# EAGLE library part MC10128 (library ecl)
ECL DEVICE

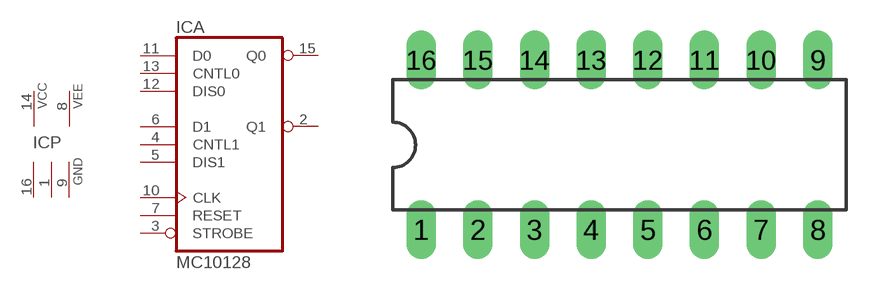
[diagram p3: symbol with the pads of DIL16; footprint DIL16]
Designator prefix IC; gates P=2PWR3GND A=MC10128

## MC10128  [DIL16]
1  P:GND  pwr
2  A:Q1  out
3  A:STROBE  in
4  A:CNTL1  in
5  A:DIS1  in
6  A:D1  in
7  A:RESET  in
8  P:VEE  pwr
9  P:GND  pwr
10  A:CLK  in
11  A:D0  in
12  A:DIS0  in
13  A:CNTL0  in
14  P:VCC  pwr
15  A:Q0  out
16  P:GND  pwr

## Footprint DIL16 (pad centres in mm)
Dual In Line Package
drill 0.813 long: 1 -8.89,-3.81; 2 -6.35,-3.81; 3 -3.81,-3.81; 4 -1.27,-3.81; 5 1.27,-3.81; 6 3.81,-3.81; 7 6.35,-3.81; 8 8.89,-3.81; 9 8.89,3.81; 10 6.35,3.81; 11 3.81,3.81; 12 1.27,3.81; 13 -1.27,3.81; 14 -3.81,3.81; 15 -6.35,3.81; 16 -8.89,3.81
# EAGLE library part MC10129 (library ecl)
ECL DEVICE

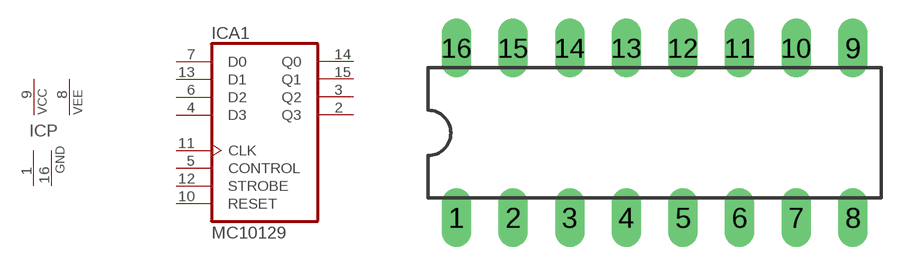
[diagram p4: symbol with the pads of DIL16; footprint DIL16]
Designator prefix IC; gates A1=MC10129 P=2PWR2GND

## MC10129  [DIL16]
1  P:GND  pwr
2  A1:Q3  out
3  A1:Q2  out
4  A1:D3  in
5  A1:CONTROL  in
6  A1:D2  in
7  A1:D0  in
8  P:VEE  pwr
9  P:VCC  pwr
10  A1:RESET  in
11  A1:CLK  in
12  A1:STROBE  in
13  A1:D1  in
14  A1:Q0  out
15  A1:Q1  out
16  P:GND  pwr

## Footprint DIL16 (pad centres in mm)
Dual In Line Package
drill 0.813 long: 1 -8.89,-3.81; 2 -6.35,-3.81; 3 -3.81,-3.81; 4 -1.27,-3.81; 5 1.27,-3.81; 6 3.81,-3.81; 7 6.35,-3.81; 8 8.89,-3.81; 9 8.89,3.81; 10 6.35,3.81; 11 3.81,3.81; 12 1.27,3.81; 13 -1.27,3.81; 14 -3.81,3.81; 15 -6.35,3.81; 16 -8.89,3.81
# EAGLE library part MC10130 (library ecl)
ECL DEVICE

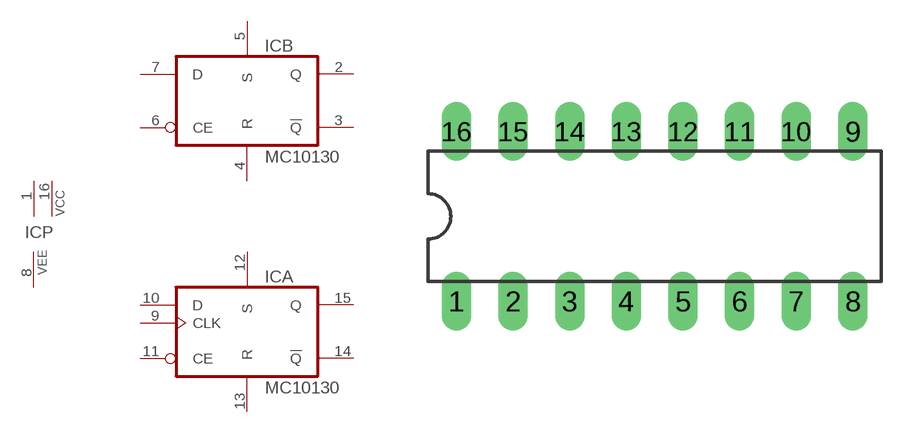
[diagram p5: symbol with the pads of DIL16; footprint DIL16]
Designator prefix IC; gates P=2VCC1VEE A=MC10130 B=MC10130 C=CLK

## MC10130  [DIL16]
1  P:VCC  pwr
2  B:Q  out
3  B:!Q  out
4  B:R  in
5  B:S  in
6  B:CE  in
7  B:D  in
8  P:VEE  pwr
9  C:CLK  in
10  A:D  in
11  A:CE  in
12  A:S  in
13  A:R  in
14  A:!Q  out
15  A:Q  out
16  P:VCC  pwr

## Footprint DIL16 (pad centres in mm)
Dual In Line Package
drill 0.813 long: 1 -8.89,-3.81; 2 -6.35,-3.81; 3 -3.81,-3.81; 4 -1.27,-3.81; 5 1.27,-3.81; 6 3.81,-3.81; 7 6.35,-3.81; 8 8.89,-3.81; 9 8.89,3.81; 10 6.35,3.81; 11 3.81,3.81; 12 1.27,3.81; 13 -1.27,3.81; 14 -3.81,3.81; 15 -6.35,3.81; 16 -8.89,3.81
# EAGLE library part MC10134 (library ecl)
ECL DEVICE

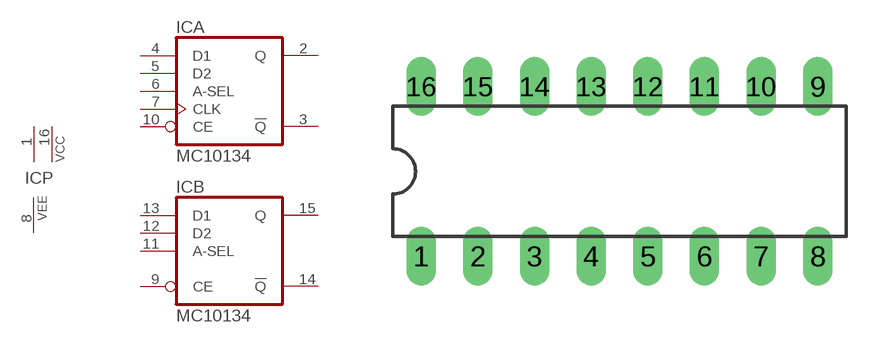
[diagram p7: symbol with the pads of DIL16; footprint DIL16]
Designator prefix IC; gates P=2VCC1VEE A=MC10134 B=MC10134 A1=CLK

## MC10134  [DIL16]
1  P:VCC  pwr
2  A:Q  out
3  A:!Q  out
4  A:D1  in
5  A:D2  in
6  A:A-SEL  in
7  A1:CLK  in
8  P:VEE  pwr
9  B:CE  in
10  A:CE  in
11  B:A-SEL  in
12  B:D2  in
13  B:D1  in
14  B:!Q  out
15  B:Q  out
16  P:VCC  pwr

## Footprint DIL16 (pad centres in mm)
Dual In Line Package
drill 0.813 long: 1 -8.89,-3.81; 2 -6.35,-3.81; 3 -3.81,-3.81; 4 -1.27,-3.81; 5 1.27,-3.81; 6 3.81,-3.81; 7 6.35,-3.81; 8 8.89,-3.81; 9 8.89,3.81; 10 6.35,3.81; 11 3.81,3.81; 12 1.27,3.81; 13 -1.27,3.81; 14 -3.81,3.81; 15 -6.35,3.81; 16 -8.89,3.81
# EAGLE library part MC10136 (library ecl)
ECL DEVICE

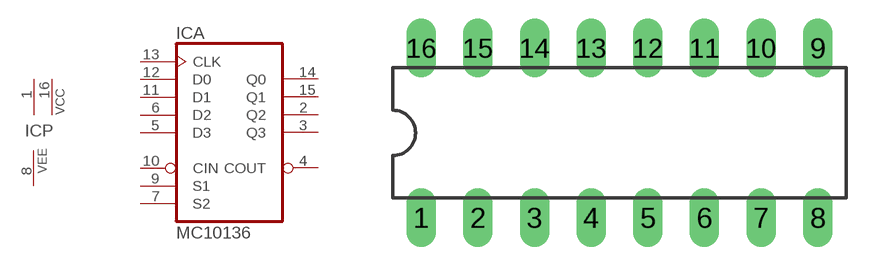
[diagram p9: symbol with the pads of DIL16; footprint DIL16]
Designator prefix IC; gates A=MC10136 P=2VCC1VEE

## MC10136  [DIL16]
1  P:VCC  pwr
2  A:Q2  out
3  A:Q3  out
4  A:COUT  out
5  A:D3  in
6  A:D2  in
7  A:S2  in
8  P:VEE  pwr
9  A:S1  in
10  A:CIN  in
11  A:D1  in
12  A:D0  in
13  A:CLK  in
14  A:Q0  out
15  A:Q1  out
16  P:VCC  pwr

## Footprint DIL16 (pad centres in mm)
Dual In Line Package
drill 0.813 long: 1 -8.89,-3.81; 2 -6.35,-3.81; 3 -3.81,-3.81; 4 -1.27,-3.81; 5 1.27,-3.81; 6 3.81,-3.81; 7 6.35,-3.81; 8 8.89,-3.81; 9 8.89,3.81; 10 6.35,3.81; 11 3.81,3.81; 12 1.27,3.81; 13 -1.27,3.81; 14 -3.81,3.81; 15 -6.35,3.81; 16 -8.89,3.81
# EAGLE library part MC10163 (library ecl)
ECL DEVICE

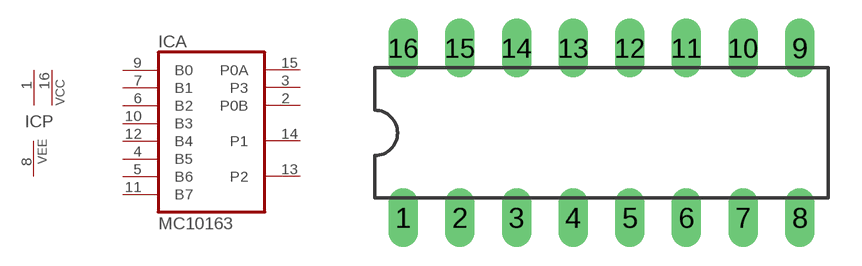
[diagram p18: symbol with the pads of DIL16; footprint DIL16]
Designator prefix IC; gates A=MC10163 P=2VCC1VEE

## MC10163  [DIL16]
1  P:VCC  pwr
2  A:P0B  out
3  A:P3  out
4  A:B5  in
5  A:B6  in
6  A:B2  in
7  A:B1  in
8  P:VEE  pwr
9  A:B0  in
10  A:B3  in
11  A:B7  in
12  A:B4  in
13  A:P2  out
14  A:P1  out
15  A:P0A  out
16  P:VCC  pwr

## Footprint DIL16 (pad centres in mm)
Dual In Line Package
drill 0.813 long: 1 -8.89,-3.81; 2 -6.35,-3.81; 3 -3.81,-3.81; 4 -1.27,-3.81; 5 1.27,-3.81; 6 3.81,-3.81; 7 6.35,-3.81; 8 8.89,-3.81; 9 8.89,3.81; 10 6.35,3.81; 11 3.81,3.81; 12 1.27,3.81; 13 -1.27,3.81; 14 -3.81,3.81; 15 -6.35,3.81; 16 -8.89,3.81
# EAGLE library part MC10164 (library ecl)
ECL DEVICE

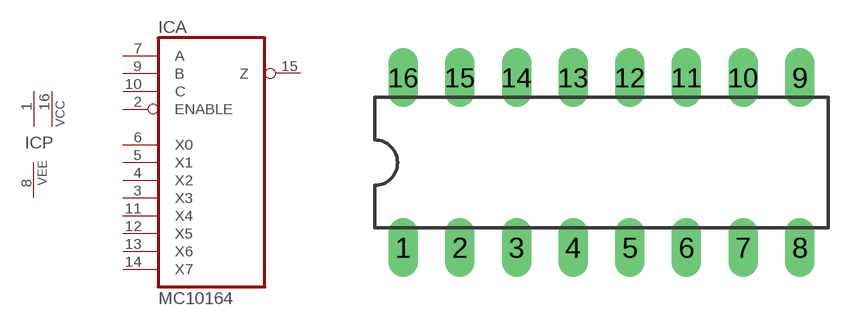
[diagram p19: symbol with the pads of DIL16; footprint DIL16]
Designator prefix IC; gates A=MC10164 P=2VCC1VEE

## MC10164  [DIL16]
1  P:VCC  pwr
2  A:ENABLE  in
3  A:X3  in
4  A:X2  in
5  A:X1  in
6  A:X0  in
7  A:A  in
8  P:VEE  pwr
9  A:B  in
10  A:C  in
11  A:X4  in
12  A:X5  in
13  A:X6  in
14  A:X7  in
15  A:Z  out
16  P:VCC  pwr

## Footprint DIL16 (pad centres in mm)
Dual In Line Package
drill 0.813 long: 1 -8.89,-3.81; 2 -6.35,-3.81; 3 -3.81,-3.81; 4 -1.27,-3.81; 5 1.27,-3.81; 6 3.81,-3.81; 7 6.35,-3.81; 8 8.89,-3.81; 9 8.89,3.81; 10 6.35,3.81; 11 3.81,3.81; 12 1.27,3.81; 13 -1.27,3.81; 14 -3.81,3.81; 15 -6.35,3.81; 16 -8.89,3.81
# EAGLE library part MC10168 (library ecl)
ECL DEVICE

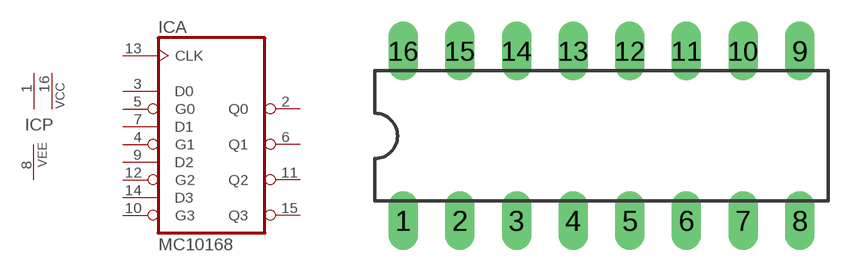
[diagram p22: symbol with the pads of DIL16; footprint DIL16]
Designator prefix IC; gates A=MC10168 P=2VCC1VEE

## MC10168  [DIL16]
1  P:VCC  pwr
2  A:Q0  out
3  A:D0  in
4  A:G1  in
5  A:G0  in
6  A:Q1  out
7  A:D1  in
8  P:VEE  pwr
9  A:D2  in
10  A:G3  in
11  A:Q2  out
12  A:G2  in
13  A:CLK  in
14  A:D3  in
15  A:Q3  out
16  P:VCC  pwr

## Footprint DIL16 (pad centres in mm)
Dual In Line Package
drill 0.813 long: 1 -8.89,-3.81; 2 -6.35,-3.81; 3 -3.81,-3.81; 4 -1.27,-3.81; 5 1.27,-3.81; 6 3.81,-3.81; 7 6.35,-3.81; 8 8.89,-3.81; 9 8.89,3.81; 10 6.35,3.81; 11 3.81,3.81; 12 1.27,3.81; 13 -1.27,3.81; 14 -3.81,3.81; 15 -6.35,3.81; 16 -8.89,3.81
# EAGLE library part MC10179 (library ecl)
ECL DEVICE

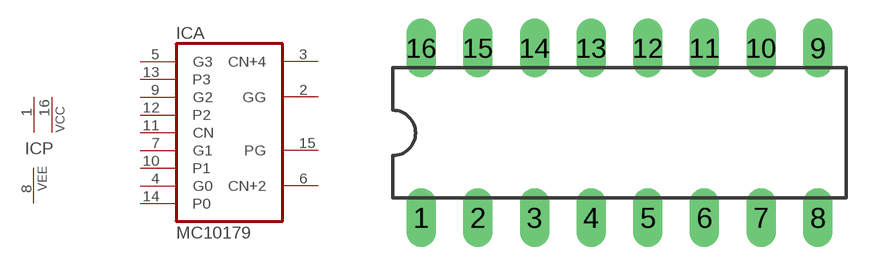
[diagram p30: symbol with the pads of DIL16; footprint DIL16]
Designator prefix IC; gates A=MC10179 P=2VCC1VEE

## MC10179  [DIL16]
1  P:VCC  pwr
2  A:GG  out
3  A:CN+4  out
4  A:G0  in
5  A:G3  in
6  A:CN+2  out
7  A:G1  in
8  P:VEE  pwr
9  A:G2  in
10  A:P1  in
11  A:CN  in
12  A:P2  in
13  A:P3  in
14  A:P0  in
15  A:PG  out
16  P:VCC  pwr

## Footprint DIL16 (pad centres in mm)
Dual In Line Package
drill 0.813 long: 1 -8.89,-3.81; 2 -6.35,-3.81; 3 -3.81,-3.81; 4 -1.27,-3.81; 5 1.27,-3.81; 6 3.81,-3.81; 7 6.35,-3.81; 8 8.89,-3.81; 9 8.89,3.81; 10 6.35,3.81; 11 3.81,3.81; 12 1.27,3.81; 13 -1.27,3.81; 14 -3.81,3.81; 15 -6.35,3.81; 16 -8.89,3.81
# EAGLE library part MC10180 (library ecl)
ECL DEVICE

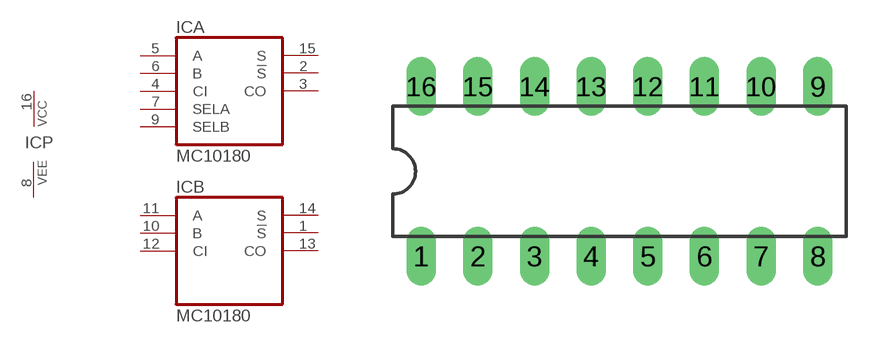
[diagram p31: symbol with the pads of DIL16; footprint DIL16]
Designator prefix IC; gates P=1VCC1VEE A=MC10180 B=MC10180 A1=SELAB

## MC10180  [DIL16]
1  B:!S  out
2  A:!S  out
3  A:CO  out
4  A:CI  in
5  A:A  in
6  A:B  in
7  A1:SELA  in
8  P:VEE  pwr
9  A1:SELB  in
10  B:B  in
11  B:A  in
12  B:CI  in
13  B:CO  out
14  B:S  out
15  A:S  out
16  P:VCC  pwr

## Footprint DIL16 (pad centres in mm)
Dual In Line Package
drill 0.813 long: 1 -8.89,-3.81; 2 -6.35,-3.81; 3 -3.81,-3.81; 4 -1.27,-3.81; 5 1.27,-3.81; 6 3.81,-3.81; 7 6.35,-3.81; 8 8.89,-3.81; 9 8.89,3.81; 10 6.35,3.81; 11 3.81,3.81; 12 1.27,3.81; 13 -1.27,3.81; 14 -3.81,3.81; 15 -6.35,3.81; 16 -8.89,3.81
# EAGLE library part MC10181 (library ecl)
ECL DEVICE

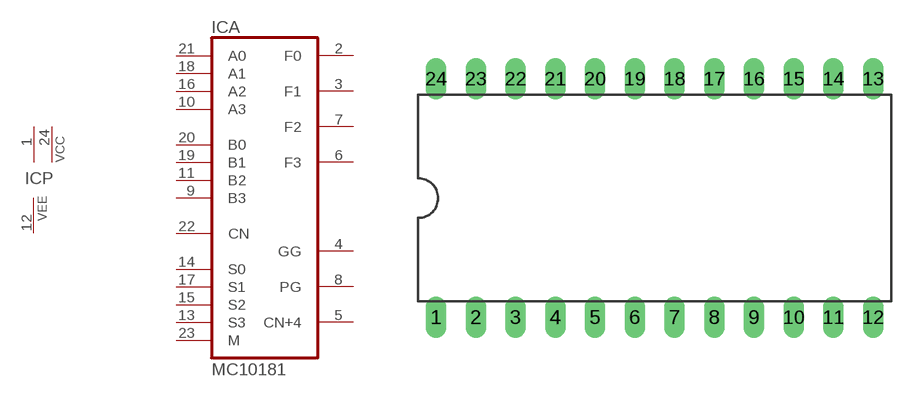
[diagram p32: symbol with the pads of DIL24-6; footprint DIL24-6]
Designator prefix IC; gates A=MC10181 P=2VCC1VEE

## MC10181  [DIL24-6]
1  P:VCC  pwr
2  A:F0  out
3  A:F1  out
4  A:GG  out
5  A:CN+4  out
6  A:F3  out
7  A:F2  out
8  A:PG  out
9  A:B3  in
10  A:A3  in
11  A:B2  in
12  P:VEE  pwr
13  A:S3  in
14  A:S0  in
15  A:S2  in
16  A:A2  in
17  A:S1  in
18  A:A1  in
19  A:B1  in
20  A:B0  in
21  A:A0  in
22  A:CN  in
23  A:M  in
24  P:VCC  pwr

## Footprint DIL24-6 (pad centres in mm)
Dual In Line Package 0.6 inch
drill 0.813 long: 1 -13.97,-7.62; 2 -11.43,-7.62; 3 -8.89,-7.62; 4 -6.35,-7.62; 5 -3.81,-7.62; 6 -1.27,-7.62; 7 1.27,-7.62; 8 3.81,-7.62; 9 6.35,-7.62; 10 8.89,-7.62; 11 11.43,-7.62; 12 13.97,-7.62; 13 13.97,7.62; 14 11.43,7.62; 15 8.89,7.62; 16 6.35,7.62; 17 3.81,7.62; 18 1.27,7.62; 19 -1.27,7.62; 20 -3.81,7.62; 21 -6.35,7.62; 22 -8.89,7.62; 23 -11.43,7.62; 24 -13.97,7.62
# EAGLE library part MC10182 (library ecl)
ECL DEVICE

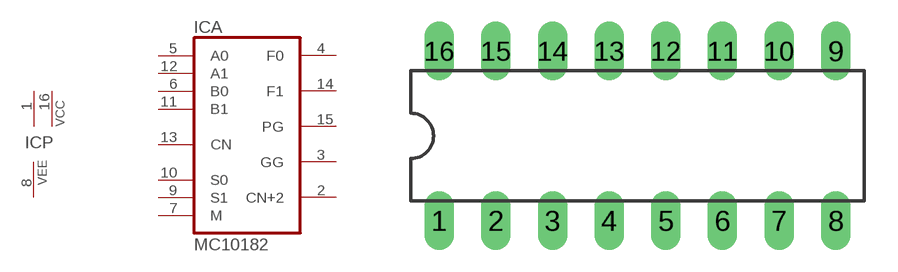
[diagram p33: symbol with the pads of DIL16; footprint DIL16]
Designator prefix IC; gates A=MC10182 P=2VCC1VEE

## MC10182  [DIL16]
1  P:VCC  pwr
2  A:CN+2  out
3  A:GG  out
4  A:F0  out
5  A:A0  in
6  A:B0  in
7  A:M  in
8  P:VEE  pwr
9  A:S1  in
10  A:S0  in
11  A:B1  in
12  A:A1  in
13  A:CN  in
14  A:F1  out
15  A:PG  out
16  P:VCC  pwr

## Footprint DIL16 (pad centres in mm)
Dual In Line Package
drill 0.813 long: 1 -8.89,-3.81; 2 -6.35,-3.81; 3 -3.81,-3.81; 4 -1.27,-3.81; 5 1.27,-3.81; 6 3.81,-3.81; 7 6.35,-3.81; 8 8.89,-3.81; 9 8.89,3.81; 10 6.35,3.81; 11 3.81,3.81; 12 1.27,3.81; 13 -1.27,3.81; 14 -3.81,3.81; 15 -6.35,3.81; 16 -8.89,3.81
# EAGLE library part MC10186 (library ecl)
ECL DEVICE

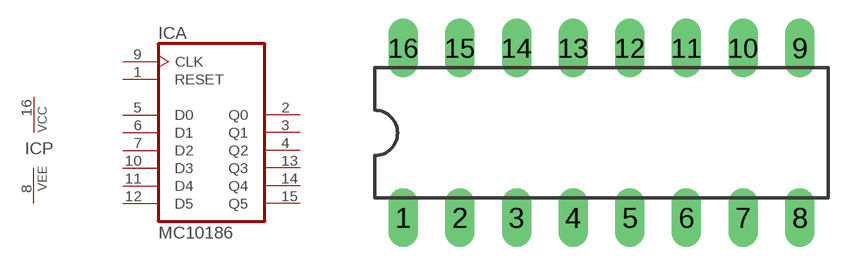
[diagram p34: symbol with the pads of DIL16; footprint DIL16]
Designator prefix IC; gates A=MC10186 P=1VCC1VEE

## MC10186  [DIL16]
1  A:RESET  in
2  A:Q0  out
3  A:Q1  out
4  A:Q2  out
5  A:D0  in
6  A:D1  in
7  A:D2  in
8  P:VEE  pwr
9  A:CLK  in
10  A:D3  in
11  A:D4  in
12  A:D5  in
13  A:Q3  out
14  A:Q4  out
15  A:Q5  out
16  P:VCC  pwr

## Footprint DIL16 (pad centres in mm)
Dual In Line Package
drill 0.813 long: 1 -8.89,-3.81; 2 -6.35,-3.81; 3 -3.81,-3.81; 4 -1.27,-3.81; 5 1.27,-3.81; 6 3.81,-3.81; 7 6.35,-3.81; 8 8.89,-3.81; 9 8.89,3.81; 10 6.35,3.81; 11 3.81,3.81; 12 1.27,3.81; 13 -1.27,3.81; 14 -3.81,3.81; 15 -6.35,3.81; 16 -8.89,3.81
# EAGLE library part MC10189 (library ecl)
ECL DEVICE

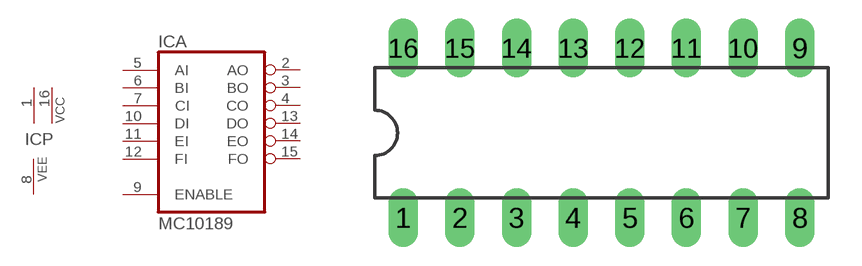
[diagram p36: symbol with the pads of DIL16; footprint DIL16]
Designator prefix IC; gates A=MC10189 P=2VCC1VEE

## MC10189  [DIL16]
1  P:VCC  pwr
2  A:AO  out
3  A:BO  out
4  A:CO  out
5  A:AI  in
6  A:BI  in
7  A:CI  in
8  P:VEE  pwr
9  A:ENABLE  in
10  A:DI  in
11  A:EI  in
12  A:FI  in
13  A:DO  out
14  A:EO  out
15  A:FO  out
16  P:VCC  pwr

## Footprint DIL16 (pad centres in mm)
Dual In Line Package
drill 0.813 long: 1 -8.89,-3.81; 2 -6.35,-3.81; 3 -3.81,-3.81; 4 -1.27,-3.81; 5 1.27,-3.81; 6 3.81,-3.81; 7 6.35,-3.81; 8 8.89,-3.81; 9 8.89,3.81; 10 6.35,3.81; 11 3.81,3.81; 12 1.27,3.81; 13 -1.27,3.81; 14 -3.81,3.81; 15 -6.35,3.81; 16 -8.89,3.81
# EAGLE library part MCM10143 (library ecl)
ECL DEVICE

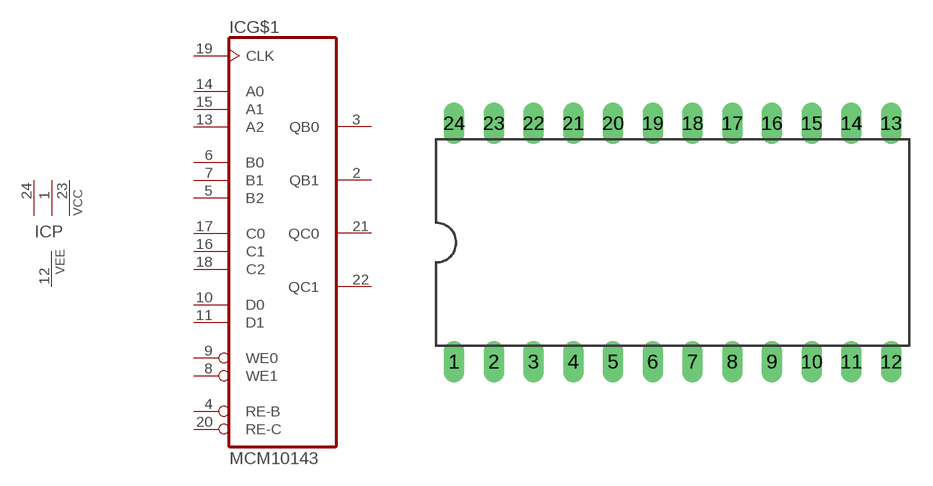
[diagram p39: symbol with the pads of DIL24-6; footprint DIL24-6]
Designator prefix IC; gates G$1=MCM10143 P=3VCC1VEE

## MCM10143  [DIL24-6]
1  P:VCC  pwr
2  G$1:QB1  out
3  G$1:QB0  out
4  G$1:RE-B  in
5  G$1:B2  in
6  G$1:B0  in
7  G$1:B1  in
8  G$1:WE1  in
9  G$1:WE0  in
10  G$1:D0  in
11  G$1:D1  in
12  P:VEE  pwr
13  G$1:A2  in
14  G$1:A0  in
15  G$1:A1  in
16  G$1:C1  in
17  G$1:C0  in
18  G$1:C2  in
19  G$1:CLK  in
20  G$1:RE-C  in
21  G$1:QC0  out
22  G$1:QC1  out
23  P:VCC  pwr
24  P:VCC  pwr

## Footprint DIL24-6 (pad centres in mm)
Dual In Line Package 0.6 inch
drill 0.813 long: 1 -13.97,-7.62; 2 -11.43,-7.62; 3 -8.89,-7.62; 4 -6.35,-7.62; 5 -3.81,-7.62; 6 -1.27,-7.62; 7 1.27,-7.62; 8 3.81,-7.62; 9 6.35,-7.62; 10 8.89,-7.62; 11 11.43,-7.62; 12 13.97,-7.62; 13 13.97,7.62; 14 11.43,7.62; 15 8.89,7.62; 16 6.35,7.62; 17 3.81,7.62; 18 1.27,7.62; 19 -1.27,7.62; 20 -3.81,7.62; 21 -6.35,7.62; 22 -8.89,7.62; 23 -11.43,7.62; 24 -13.97,7.62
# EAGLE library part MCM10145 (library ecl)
ECL DEVICE

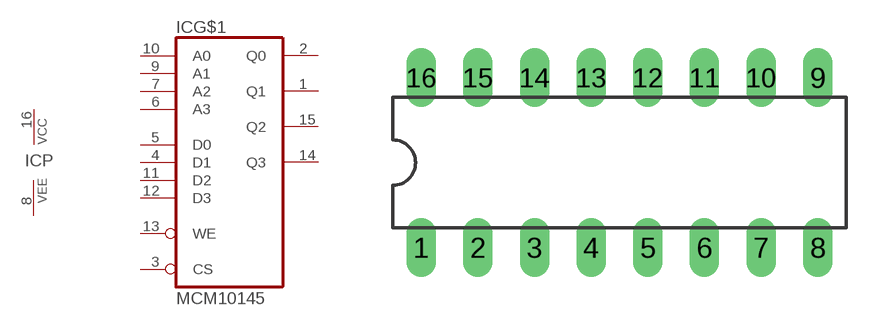
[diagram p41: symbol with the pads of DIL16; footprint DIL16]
Designator prefix IC; gates G$1=MCM10145 P=1VCC1VEE

## MCM10145  [DIL16]
1  G$1:Q1  out
2  G$1:Q0  out
3  G$1:CS  in
4  G$1:D1  in
5  G$1:D0  in
6  G$1:A3  in
7  G$1:A2  in
8  P:VEE  pwr
9  G$1:A1  in
10  G$1:A0  in
11  G$1:D2  in
12  G$1:D3  in
13  G$1:WE  in
14  G$1:Q3  out
15  G$1:Q2  out
16  P:VCC  pwr

## Footprint DIL16 (pad centres in mm)
Dual In Line Package
drill 0.813 long: 1 -8.89,-3.81; 2 -6.35,-3.81; 3 -3.81,-3.81; 4 -1.27,-3.81; 5 1.27,-3.81; 6 3.81,-3.81; 7 6.35,-3.81; 8 8.89,-3.81; 9 8.89,3.81; 10 6.35,3.81; 11 3.81,3.81; 12 1.27,3.81; 13 -1.27,3.81; 14 -3.81,3.81; 15 -6.35,3.81; 16 -8.89,3.81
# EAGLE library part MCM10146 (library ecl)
ECL DEVICE

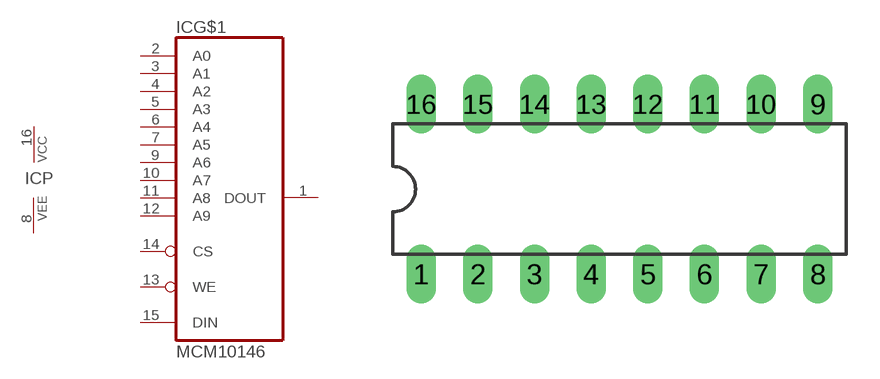
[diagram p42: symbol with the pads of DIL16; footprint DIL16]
Designator prefix IC; gates G$1=MCM10146 P=1VCC1VEE

## MCM10146  [DIL16]
1  G$1:DOUT  out
2  G$1:A0  in
3  G$1:A1  in
4  G$1:A2  in
5  G$1:A3  in
6  G$1:A4  in
7  G$1:A5  in
8  P:VEE  pwr
9  G$1:A6  in
10  G$1:A7  in
11  G$1:A8  in
12  G$1:A9  in
13  G$1:WE  in
14  G$1:CS  in
15  G$1:DIN  in
16  P:VCC  pwr

## Footprint DIL16 (pad centres in mm)
Dual In Line Package
drill 0.813 long: 1 -8.89,-3.81; 2 -6.35,-3.81; 3 -3.81,-3.81; 4 -1.27,-3.81; 5 1.27,-3.81; 6 3.81,-3.81; 7 6.35,-3.81; 8 8.89,-3.81; 9 8.89,3.81; 10 6.35,3.81; 11 3.81,3.81; 12 1.27,3.81; 13 -1.27,3.81; 14 -3.81,3.81; 15 -6.35,3.81; 16 -8.89,3.81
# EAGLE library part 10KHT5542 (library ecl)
ECL DEVICE

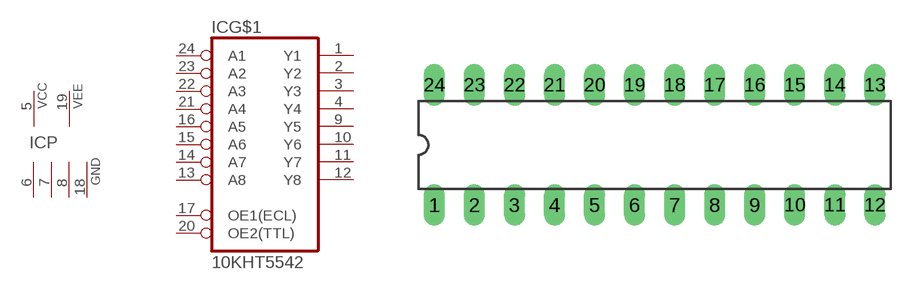
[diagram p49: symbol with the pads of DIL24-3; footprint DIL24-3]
Designator prefix IC; gates G$1=5542 P=2PWR4GND

## 10KHT5542  [DIL24-3]
1  G$1:Y1  out
2  G$1:Y2  out
3  G$1:Y3  out
4  G$1:Y4  out
5  P:VCC  pwr
6  P:GND  pwr
7  P:GND  pwr
8  P:GND  pwr
9  G$1:Y5  out
10  G$1:Y6  out
11  G$1:Y7  out
12  G$1:Y8  out
13  G$1:A8  in
14  G$1:A7  in
15  G$1:A6  in
16  G$1:A5  in
17  G$1:OE1(ECL)  in
18  P:GND  pwr
19  P:VEE  pwr
20  G$1:OE2(TTL)  in
21  G$1:A4  in
22  G$1:A3  in
23  G$1:A2  in
24  G$1:A1  in

## Footprint DIL24-3 (pad centres in mm)
Dual In Line Package 0.3 inch
drill 0.813 long: 1 -13.97,-3.81; 2 -11.43,-3.81; 3 -8.89,-3.81; 4 -6.35,-3.81; 5 -3.81,-3.81; 6 -1.27,-3.81; 7 1.27,-3.81; 8 3.81,-3.81; 9 6.35,-3.81; 10 8.89,-3.81; 11 11.43,-3.81; 12 13.97,-3.81; 13 13.97,3.81; 14 11.43,3.81; 15 8.89,3.81; 16 6.35,3.81; 17 3.81,3.81; 18 1.27,3.81; 19 -1.27,3.81; 20 -3.81,3.81; 21 -6.35,3.81; 22 -8.89,3.81; 23 -11.43,3.81; 24 -13.97,3.81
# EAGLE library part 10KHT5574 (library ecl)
ECL DEVICE

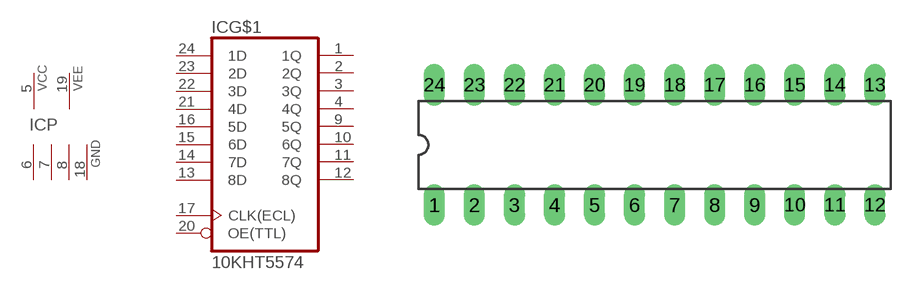
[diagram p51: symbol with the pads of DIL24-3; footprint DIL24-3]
Designator prefix IC; gates G$1=5574 P=2PWR4GND

## 10KHT5574  [DIL24-3]
1  G$1:1Q  hiz
2  G$1:2Q  hiz
3  G$1:3Q  hiz
4  G$1:4Q  hiz
5  P:VCC  pwr
6  P:GND  pwr
7  P:GND  pwr
8  P:GND  pwr
9  G$1:5Q  hiz
10  G$1:6Q  hiz
11  G$1:7Q  hiz
12  G$1:8Q  hiz
13  G$1:8D  in
14  G$1:7D  in
15  G$1:6D  in
16  G$1:5D  in
17  G$1:CLK(ECL)  in
18  P:GND  pwr
19  P:VEE  pwr
20  G$1:OE(TTL)  in
21  G$1:4D  in
22  G$1:3D  in
23  G$1:2D  in
24  G$1:1D  in

## Footprint DIL24-3 (pad centres in mm)
Dual In Line Package 0.3 inch
drill 0.813 long: 1 -13.97,-3.81; 2 -11.43,-3.81; 3 -8.89,-3.81; 4 -6.35,-3.81; 5 -3.81,-3.81; 6 -1.27,-3.81; 7 1.27,-3.81; 8 3.81,-3.81; 9 6.35,-3.81; 10 8.89,-3.81; 11 11.43,-3.81; 12 13.97,-3.81; 13 13.97,3.81; 14 11.43,3.81; 15 8.89,3.81; 16 6.35,3.81; 17 3.81,3.81; 18 1.27,3.81; 19 -1.27,3.81; 20 -3.81,3.81; 21 -6.35,3.81; 22 -8.89,3.81; 23 -11.43,3.81; 24 -13.97,3.81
